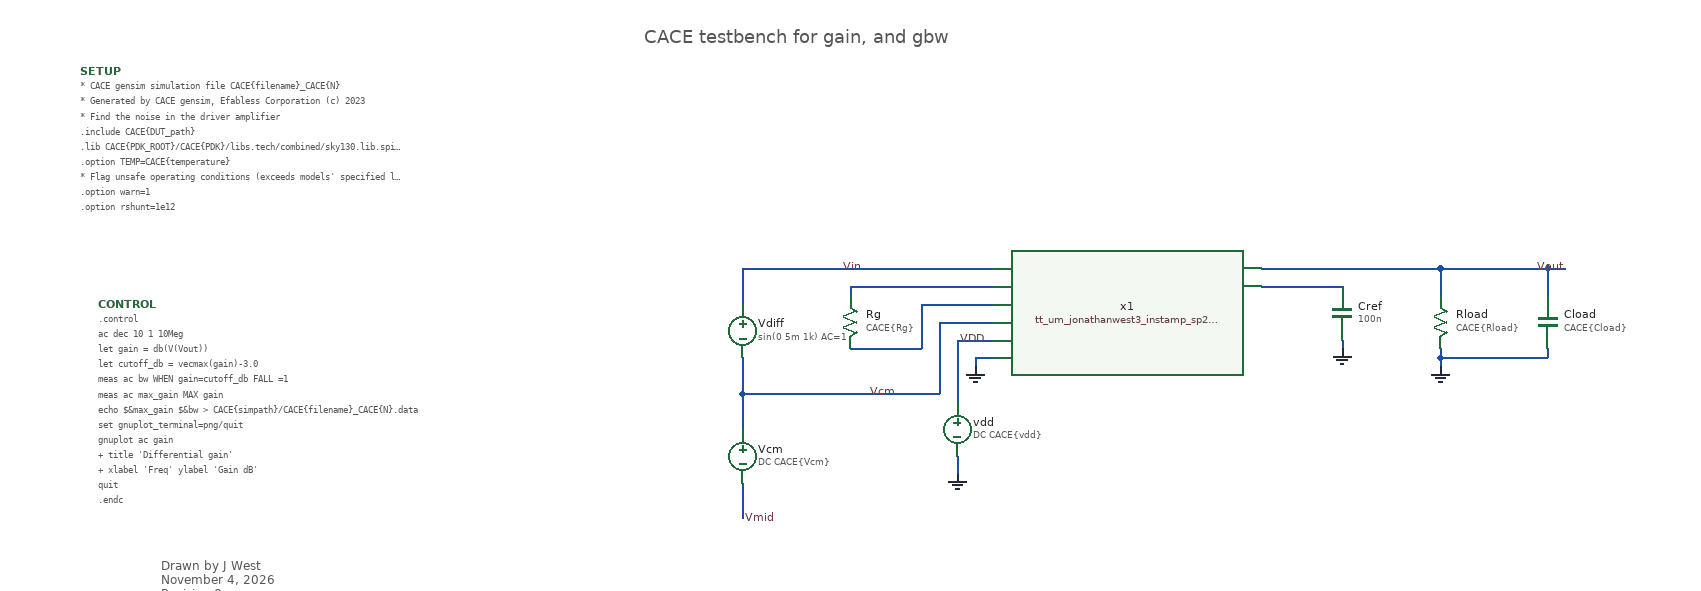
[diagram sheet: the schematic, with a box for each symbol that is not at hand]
v {xschem version=3.4.8RC file_version=1.3}
G {}
K {}
V {}
S {}
F {}
E {}
T {CACE testbench for gain, and gbw} -390 -640 0 0 0.6 0.6 {}
T {Drawn by J West
November 4, 2026
Revision 0
} -930 -50 0 0 0.4 0.4 {}
N 620 -370 640 -370 {
lab=Vout}
N -160 -350 -160 -340 {lab=#net1}
N -160 -350 0 -350 {lab=#net1}
N -160 -280 -80 -280 {lab=#net2}
N -80 -310 -80 -280 {lab=#net2}
N -60 -290 -60 -230 {lab=Vcm}
N -280 -230 -60 -230 {lab=Vcm}
N 300 -350 390 -350 {lab=#net3}
N 390 -290 390 -280 {lab=GND}
N -40 -160 -40 -140 {lab=GND}
N -40 -240 -40 -220 {lab=VDD}
N -280 -130 -280 -120 {lab=Vmid}
N -280 -370 0 -370 {lab=Vin}
N -40 -290 0 -290 {lab=VDD}
N 500 -270 500 -260 {lab=GND}
N 500 -280 500 -270 {lab=GND}
N 550 -270 620 -270 {lab=GND}
N 620 -280 620 -270 {lab=GND}
N 620 -370 620 -340 {lab=Vout}
N 500 -370 500 -340 {lab=Vout}
N -280 -370 -280 -330 {lab=Vin}
N -280 -270 -280 -230 {lab=Vcm}
N -280 -230 -280 -190 {lab=Vcm}
N 550 -370 620 -370 {
lab=Vout}
N 300 -370 500 -370 {
lab=Vout}
N -40 -290 -40 -240 {lab=VDD}
N 500 -370 550 -370 {lab=Vout}
N 500 -270 550 -270 {lab=GND}
N -280 -120 -280 -90 {lab=Vmid}
N -80 -330 -80 -310 {lab=#net2}
N -80 -330 0 -330 {lab=#net2}
N -60 -310 -60 -290 {lab=Vcm}
N -60 -310 0 -310 {lab=Vcm}
N -20 -270 -20 -260 {lab=GND}
N -20 -270 0 -270 {lab=GND}
C {devices/code_shown.sym} -1000 -330 0 0 {name=CONTROL only_toplevel=false value=".control
ac dec 10 1 10Meg
let gain = db(V(Vout))
let cutoff_db = vecmax(gain)-3.0
meas ac bw WHEN gain=cutoff_db FALL =1
meas ac max_gain MAX gain
echo $&max_gain $&bw > CACE\{simpath\}/CACE\{filename\}_CACE\{N\}.data
set gnuplot_terminal=png/quit
gnuplot ac gain
+ title 'Differential gain'
+ xlabel 'Freq' ylabel 'Gain dB'

quit
.endc
"}
C {devices/code_shown.sym} -1020 -590 0 0 {name=SETUP only_toplevel=false value="* CACE gensim simulation file CACE\{filename\}_CACE\{N\}
* Generated by CACE gensim, Efabless Corporation (c) 2023
* Find the noise in the driver amplifier

.include CACE\{DUT_path\}

.lib CACE\{PDK_ROOT\}/CACE\{PDK\}/libs.tech/combined/sky130.lib.spice CACE\{corner\}

.option TEMP=CACE\{temperature\}
* Flag unsafe operating conditions (exceeds models' specified limits)
.option warn=1
.option rshunt=1e12
"}
C {devices/vsource.sym} -280 -160 0 0 {name=Vcm value="DC CACE\{Vcm\}" savecurrent=false}
C {devices/lab_wire.sym} 640 -370 0 0 {name=p25 sig_type=std_logic lab=Vout}
C {devices/vsource.sym} -40 -190 0 0 {name=vdd value="DC CACE\{vdd\}" savecurrent=false}
C {devices/lab_wire.sym} -140 -230 0 1 {name=p4 sig_type=std_logic lab=Vcm}
C {devices/res.sym} -160 -310 0 0 {name=Rg
value=CACE\{Rg\}
device=resistor}
C {capa.sym} 390 -320 0 0 {name=Cref
m=1
value=100n
footprint=1206
device="ceramic capacitor"}
C {devices/gnd.sym} 390 -280 0 0 {name=l2 lab=GND}
C {devices/gnd.sym} -40 -140 0 0 {name=l1 lab=GND}
C {devices/gnd.sym} -20 -260 0 0 {name=l5 lab=GND}
C {devices/lab_wire.sym} -40 -290 0 1 {name=p5 sig_type=std_logic lab=VDD}
C {devices/lab_wire.sym} -170 -370 0 1 {name=p6 sig_type=std_logic lab=Vin}
C {devices/res.sym} 500 -310 0 0 {name=Rload
value=CACE\{Rload\}
device=resistor}
C {capa.sym} 620 -310 0 0 {name=Cload
m=1
value=CACE\{Cload\}
footprint=1206
device="ceramic capacitor"}
C {devices/gnd.sym} 500 -260 0 0 {name=l3 lab=GND}
C {vsource.sym} -280 -300 0 0 {name=Vdiff value="sin(0 5m 1k) AC=1"}
C {devices/lab_wire.sym} -280 -90 0 1 {name=p2 sig_type=std_logic lab=Vmid}
C {tt_um_jonathanwest3_instamp_sp2026.sym} 150 -80 0 0 {name=x1}
